VERSION 5.7 ;
  NOWIREEXTENSIONATPIN ON ;
  DIVIDERCHAR "/" ;
  BUSBITCHARS "[]" ;
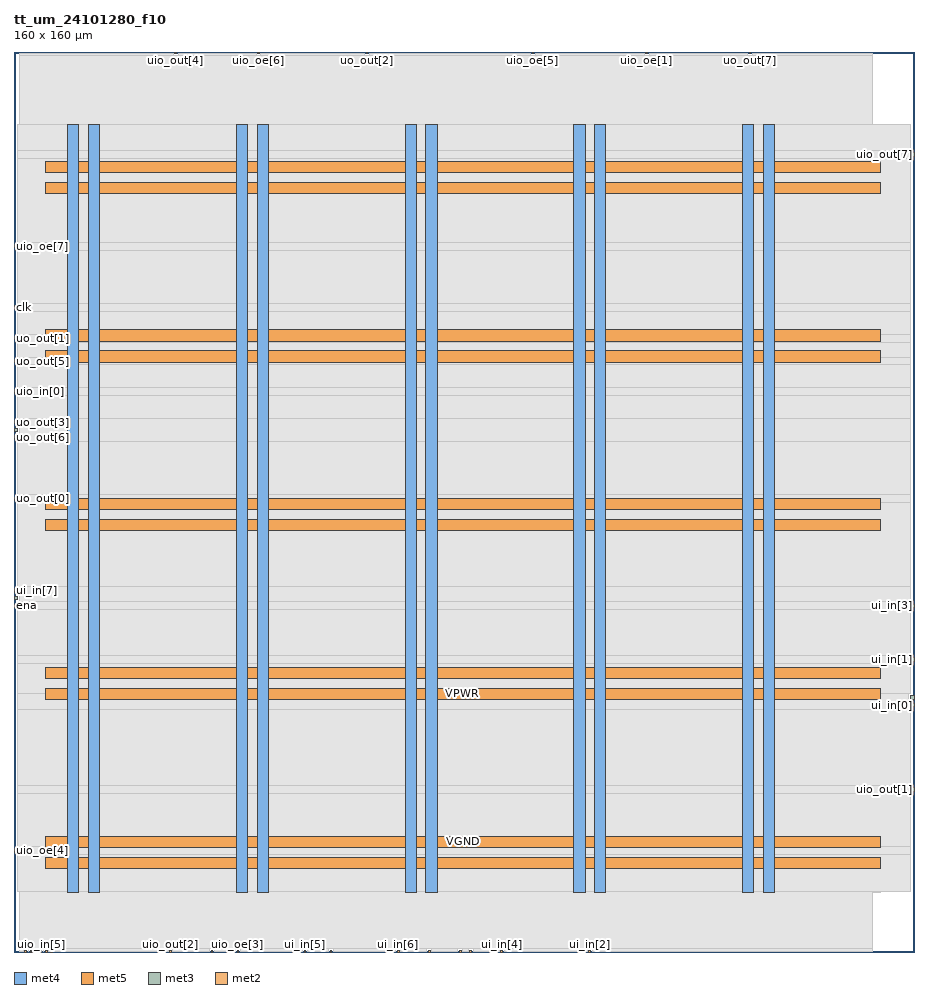
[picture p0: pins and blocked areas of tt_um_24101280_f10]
MACRO tt_um_24101280_f10
  CLASS BLOCK ;
  FOREIGN tt_um_24101280_f10 ;
  ORIGIN 0.000 0.000 ;
  SIZE 160.000 BY 160.000 ;
  PIN VGND
    DIRECTION INOUT ;
    USE GROUND ;
    PORT
      LAYER met4 ;
        RECT 13.220 10.640 15.220 147.120 ;
    END
    PORT
      LAYER met4 ;
        RECT 43.220 10.640 45.220 147.120 ;
    END
    PORT
      LAYER met4 ;
        RECT 73.220 10.640 75.220 147.120 ;
    END
    PORT
      LAYER met4 ;
        RECT 103.220 10.640 105.220 147.120 ;
    END
    PORT
      LAYER met4 ;
        RECT 133.220 10.640 135.220 147.120 ;
    END
    PORT
      LAYER met5 ;
        RECT 5.520 18.580 154.100 20.580 ;
    END
    PORT
      LAYER met5 ;
        RECT 5.520 48.580 154.100 50.580 ;
    END
    PORT
      LAYER met5 ;
        RECT 5.520 78.580 154.100 80.580 ;
    END
    PORT
      LAYER met5 ;
        RECT 5.520 108.580 154.100 110.580 ;
    END
    PORT
      LAYER met5 ;
        RECT 5.520 138.580 154.100 140.580 ;
    END
  END VGND
  PIN VPWR
    DIRECTION INOUT ;
    USE POWER ;
    PORT
      LAYER met4 ;
        RECT 9.520 10.640 11.520 147.120 ;
    END
    PORT
      LAYER met4 ;
        RECT 39.520 10.640 41.520 147.120 ;
    END
    PORT
      LAYER met4 ;
        RECT 69.520 10.640 71.520 147.120 ;
    END
    PORT
      LAYER met4 ;
        RECT 99.520 10.640 101.520 147.120 ;
    END
    PORT
      LAYER met4 ;
        RECT 129.520 10.640 131.520 147.120 ;
    END
    PORT
      LAYER met5 ;
        RECT 5.520 14.880 154.100 16.880 ;
    END
    PORT
      LAYER met5 ;
        RECT 5.520 44.880 154.100 46.880 ;
    END
    PORT
      LAYER met5 ;
        RECT 5.520 74.880 154.100 76.880 ;
    END
    PORT
      LAYER met5 ;
        RECT 5.520 104.880 154.100 106.880 ;
    END
    PORT
      LAYER met5 ;
        RECT 5.520 134.880 154.100 136.880 ;
    END
  END VPWR
  PIN clk
    DIRECTION INPUT ;
    USE SIGNAL ;
    ANTENNAGATEAREA 0.852000 ;
    PORT
      LAYER met3 ;
        RECT 0.000 114.280 0.600 114.880 ;
    END
  END clk
  PIN ena
    DIRECTION INPUT ;
    USE SIGNAL ;
    ANTENNAGATEAREA 0.213000 ;
    PORT
      LAYER met3 ;
        RECT 0.000 61.240 0.600 61.840 ;
    END
  END ena
  PIN rst_n
    DIRECTION INPUT ;
    USE SIGNAL ;
    ANTENNAGATEAREA 0.213000 ;
    PORT
      LAYER met3 ;
        RECT 159.400 44.920 160.000 45.520 ;
    END
  END rst_n
  PIN ui_in[0]
    DIRECTION INPUT ;
    USE SIGNAL ;
    ANTENNAGATEAREA 0.213000 ;
    PORT
      LAYER met3 ;
        RECT 159.400 43.560 160.000 44.160 ;
    END
  END ui_in[0]
  PIN ui_in[1]
    DIRECTION INPUT ;
    USE SIGNAL ;
    ANTENNAGATEAREA 0.213000 ;
    PORT
      LAYER met3 ;
        RECT 159.400 51.720 160.000 52.320 ;
    END
  END ui_in[1]
  PIN ui_in[2]
    DIRECTION INPUT ;
    USE SIGNAL ;
    ANTENNAGATEAREA 0.213000 ;
    PORT
      LAYER met2 ;
        RECT 102.210 0.000 102.490 0.280 ;
    END
  END ui_in[2]
  PIN ui_in[3]
    DIRECTION INPUT ;
    USE SIGNAL ;
    ANTENNAGATEAREA 0.213000 ;
    PORT
      LAYER met3 ;
        RECT 159.400 61.240 160.000 61.840 ;
    END
  END ui_in[3]
  PIN ui_in[4]
    DIRECTION INPUT ;
    USE SIGNAL ;
    ANTENNAGATEAREA 0.213000 ;
    PORT
      LAYER met2 ;
        RECT 86.570 0.000 86.850 0.280 ;
    END
  END ui_in[4]
  PIN ui_in[5]
    DIRECTION INPUT ;
    USE SIGNAL ;
    ANTENNAGATEAREA 0.213000 ;
    PORT
      LAYER met2 ;
        RECT 51.610 0.000 51.890 0.280 ;
    END
  END ui_in[5]
  PIN ui_in[6]
    DIRECTION INPUT ;
    USE SIGNAL ;
    ANTENNAGATEAREA 0.213000 ;
    PORT
      LAYER met2 ;
        RECT 68.170 0.000 68.450 0.280 ;
    END
  END ui_in[6]
  PIN ui_in[7]
    DIRECTION INPUT ;
    USE SIGNAL ;
    ANTENNAGATEAREA 0.213000 ;
    PORT
      LAYER met3 ;
        RECT 0.000 63.960 0.600 64.560 ;
    END
  END ui_in[7]
  PIN uio_in[0]
    DIRECTION INPUT ;
    USE SIGNAL ;
    ANTENNAGATEAREA 0.213000 ;
    PORT
      LAYER met3 ;
        RECT 0.000 99.320 0.600 99.920 ;
    END
  END uio_in[0]
  PIN uio_in[1]
    DIRECTION INPUT ;
    USE SIGNAL ;
    ANTENNAGATEAREA 0.213000 ;
    PORT
      LAYER met3 ;
        RECT 0.000 62.600 0.600 63.200 ;
    END
  END uio_in[1]
  PIN uio_in[2]
    DIRECTION INPUT ;
    USE SIGNAL ;
    PORT
      LAYER met2 ;
        RECT 1.930 0.000 2.210 0.280 ;
    END
  END uio_in[2]
  PIN uio_in[3]
    DIRECTION INPUT ;
    USE SIGNAL ;
    PORT
      LAYER met2 ;
        RECT 2.850 0.000 3.130 0.280 ;
    END
  END uio_in[3]
  PIN uio_in[4]
    DIRECTION INPUT ;
    USE SIGNAL ;
    PORT
      LAYER met2 ;
        RECT 3.770 0.000 4.050 0.280 ;
    END
  END uio_in[4]
  PIN uio_in[5]
    DIRECTION INPUT ;
    USE SIGNAL ;
    PORT
      LAYER met2 ;
        RECT 4.690 0.000 4.970 0.280 ;
    END
  END uio_in[5]
  PIN uio_in[6]
    DIRECTION INPUT ;
    USE SIGNAL ;
    PORT
      LAYER met2 ;
        RECT 5.610 0.000 5.890 0.280 ;
    END
  END uio_in[6]
  PIN uio_in[7]
    DIRECTION INPUT ;
    USE SIGNAL ;
    PORT
      LAYER met2 ;
        RECT 6.530 0.000 6.810 0.280 ;
    END
  END uio_in[7]
  PIN uio_oe[0]
    DIRECTION OUTPUT ;
    USE SIGNAL ;
    PORT
      LAYER met2 ;
        RECT 35.050 0.000 35.330 0.280 ;
    END
  END uio_oe[0]
  PIN uio_oe[1]
    DIRECTION OUTPUT ;
    USE SIGNAL ;
    PORT
      LAYER met2 ;
        RECT 112.330 159.720 112.610 160.000 ;
    END
  END uio_oe[1]
  PIN uio_oe[2]
    DIRECTION OUTPUT ;
    USE SIGNAL ;
    PORT
      LAYER met2 ;
        RECT 79.210 0.000 79.490 0.280 ;
    END
  END uio_oe[2]
  PIN uio_oe[3]
    DIRECTION OUTPUT ;
    USE SIGNAL ;
    PORT
      LAYER met2 ;
        RECT 39.650 0.000 39.930 0.280 ;
    END
  END uio_oe[3]
  PIN uio_oe[4]
    DIRECTION OUTPUT ;
    USE SIGNAL ;
    PORT
      LAYER met3 ;
        RECT 0.000 17.720 0.600 18.320 ;
    END
  END uio_oe[4]
  PIN uio_oe[5]
    DIRECTION OUTPUT ;
    USE SIGNAL ;
    PORT
      LAYER met2 ;
        RECT 92.090 159.720 92.370 160.000 ;
    END
  END uio_oe[5]
  PIN uio_oe[6]
    DIRECTION OUTPUT ;
    USE SIGNAL ;
    PORT
      LAYER met2 ;
        RECT 43.330 159.720 43.610 160.000 ;
    END
  END uio_oe[6]
  PIN uio_oe[7]
    DIRECTION OUTPUT ;
    USE SIGNAL ;
    PORT
      LAYER met3 ;
        RECT 0.000 125.160 0.600 125.760 ;
    END
  END uio_oe[7]
  PIN uio_out[0]
    DIRECTION OUTPUT ;
    USE SIGNAL ;
    PORT
      LAYER met2 ;
        RECT 73.690 0.000 73.970 0.280 ;
    END
  END uio_out[0]
  PIN uio_out[1]
    DIRECTION OUTPUT ;
    USE SIGNAL ;
    PORT
      LAYER met3 ;
        RECT 159.400 28.600 160.000 29.200 ;
    END
  END uio_out[1]
  PIN uio_out[2]
    DIRECTION OUTPUT ;
    USE SIGNAL ;
    PORT
      LAYER met2 ;
        RECT 27.690 0.000 27.970 0.280 ;
    END
  END uio_out[2]
  PIN uio_out[3]
    DIRECTION OUTPUT ;
    USE SIGNAL ;
    PORT
      LAYER met2 ;
        RECT 56.210 0.000 56.490 0.280 ;
    END
  END uio_out[3]
  PIN uio_out[4]
    DIRECTION OUTPUT ;
    USE SIGNAL ;
    PORT
      LAYER met2 ;
        RECT 28.610 159.720 28.890 160.000 ;
    END
  END uio_out[4]
  PIN uio_out[5]
    DIRECTION OUTPUT ;
    USE SIGNAL ;
    PORT
      LAYER met2 ;
        RECT 85.650 0.000 85.930 0.280 ;
    END
  END uio_out[5]
  PIN uio_out[6]
    DIRECTION OUTPUT ;
    USE SIGNAL ;
    PORT
      LAYER met2 ;
        RECT 81.050 0.000 81.330 0.280 ;
    END
  END uio_out[6]
  PIN uio_out[7]
    DIRECTION OUTPUT ;
    USE SIGNAL ;
    PORT
      LAYER met3 ;
        RECT 159.400 141.480 160.000 142.080 ;
    END
  END uio_out[7]
  PIN uo_out[0]
    DIRECTION OUTPUT ;
    USE SIGNAL ;
    ANTENNADIFFAREA 0.702900 ;
    PORT
      LAYER met3 ;
        RECT 0.000 80.280 0.600 80.880 ;
    END
  END uo_out[0]
  PIN uo_out[1]
    DIRECTION OUTPUT ;
    USE SIGNAL ;
    ANTENNADIFFAREA 0.702900 ;
    PORT
      LAYER met3 ;
        RECT 0.000 108.840 0.600 109.440 ;
    END
  END uo_out[1]
  PIN uo_out[2]
    DIRECTION OUTPUT ;
    USE SIGNAL ;
    ANTENNADIFFAREA 0.702900 ;
    PORT
      LAYER met2 ;
        RECT 62.650 159.720 62.930 160.000 ;
    END
  END uo_out[2]
  PIN uo_out[3]
    DIRECTION OUTPUT ;
    USE SIGNAL ;
    ANTENNADIFFAREA 0.702900 ;
    PORT
      LAYER met3 ;
        RECT 0.000 93.880 0.600 94.480 ;
    END
  END uo_out[3]
  PIN uo_out[4]
    DIRECTION OUTPUT ;
    USE SIGNAL ;
    ANTENNADIFFAREA 0.702900 ;
    PORT
      LAYER met3 ;
        RECT 0.000 92.520 0.600 93.120 ;
    END
  END uo_out[4]
  PIN uo_out[5]
    DIRECTION OUTPUT ;
    USE SIGNAL ;
    ANTENNADIFFAREA 0.702900 ;
    PORT
      LAYER met3 ;
        RECT 0.000 104.760 0.600 105.360 ;
    END
  END uo_out[5]
  PIN uo_out[6]
    DIRECTION OUTPUT ;
    USE SIGNAL ;
    ANTENNADIFFAREA 0.702900 ;
    PORT
      LAYER met3 ;
        RECT 0.000 91.160 0.600 91.760 ;
    END
  END uo_out[6]
  PIN uo_out[7]
    DIRECTION OUTPUT ;
    USE SIGNAL ;
    PORT
      LAYER met2 ;
        RECT 130.730 159.720 131.010 160.000 ;
    END
  END uo_out[7]
  OBS
      LAYER nwell ;
        RECT 5.330 10.795 154.290 146.965 ;
      LAYER li1 ;
        RECT 5.520 10.795 154.100 146.965 ;
      LAYER met1 ;
        RECT 0.990 10.640 154.100 147.120 ;
      LAYER met2 ;
        RECT 1.010 159.440 28.330 159.720 ;
        RECT 29.170 159.440 43.050 159.720 ;
        RECT 43.890 159.440 62.370 159.720 ;
        RECT 63.210 159.440 91.810 159.720 ;
        RECT 92.650 159.440 112.050 159.720 ;
        RECT 112.890 159.440 130.450 159.720 ;
        RECT 131.290 159.440 152.630 159.720 ;
        RECT 1.010 0.560 152.630 159.440 ;
        RECT 1.010 0.070 1.650 0.560 ;
        RECT 2.490 0.070 2.570 0.560 ;
        RECT 3.410 0.070 3.490 0.560 ;
        RECT 4.330 0.070 4.410 0.560 ;
        RECT 5.250 0.070 5.330 0.560 ;
        RECT 6.170 0.070 6.250 0.560 ;
        RECT 7.090 0.070 27.410 0.560 ;
        RECT 28.250 0.070 34.770 0.560 ;
        RECT 35.610 0.070 39.370 0.560 ;
        RECT 40.210 0.070 51.330 0.560 ;
        RECT 52.170 0.070 55.930 0.560 ;
        RECT 56.770 0.070 67.890 0.560 ;
        RECT 68.730 0.070 73.410 0.560 ;
        RECT 74.250 0.070 78.930 0.560 ;
        RECT 79.770 0.070 80.770 0.560 ;
        RECT 81.610 0.070 85.370 0.560 ;
        RECT 86.210 0.070 86.290 0.560 ;
        RECT 87.130 0.070 101.930 0.560 ;
        RECT 102.770 0.070 152.630 0.560 ;
      LAYER met3 ;
        RECT 0.600 142.480 159.400 147.045 ;
        RECT 0.600 141.080 159.000 142.480 ;
        RECT 0.600 126.160 159.400 141.080 ;
        RECT 1.000 124.760 159.400 126.160 ;
        RECT 0.600 115.280 159.400 124.760 ;
        RECT 1.000 113.880 159.400 115.280 ;
        RECT 0.600 109.840 159.400 113.880 ;
        RECT 1.000 108.440 159.400 109.840 ;
        RECT 0.600 105.760 159.400 108.440 ;
        RECT 1.000 104.360 159.400 105.760 ;
        RECT 0.600 100.320 159.400 104.360 ;
        RECT 1.000 98.920 159.400 100.320 ;
        RECT 0.600 94.880 159.400 98.920 ;
        RECT 1.000 90.760 159.400 94.880 ;
        RECT 0.600 81.280 159.400 90.760 ;
        RECT 1.000 79.880 159.400 81.280 ;
        RECT 0.600 64.960 159.400 79.880 ;
        RECT 1.000 62.240 159.400 64.960 ;
        RECT 1.000 60.840 159.000 62.240 ;
        RECT 0.600 52.720 159.400 60.840 ;
        RECT 0.600 51.320 159.000 52.720 ;
        RECT 0.600 45.920 159.400 51.320 ;
        RECT 0.600 43.160 159.000 45.920 ;
        RECT 0.600 29.600 159.400 43.160 ;
        RECT 0.600 28.200 159.000 29.600 ;
        RECT 0.600 18.720 159.400 28.200 ;
        RECT 1.000 17.320 159.400 18.720 ;
        RECT 0.600 10.715 159.400 17.320 ;
  END
END tt_um_24101280_f10
END LIBRARY

